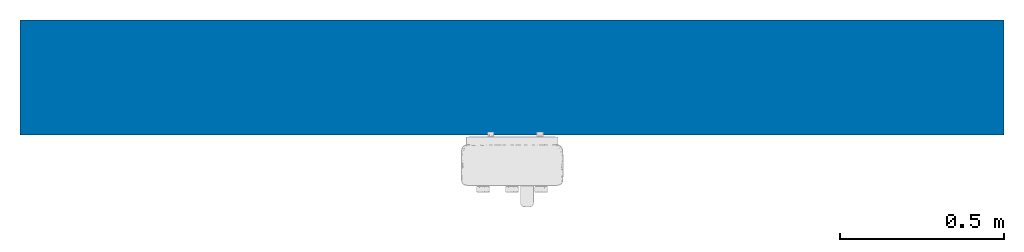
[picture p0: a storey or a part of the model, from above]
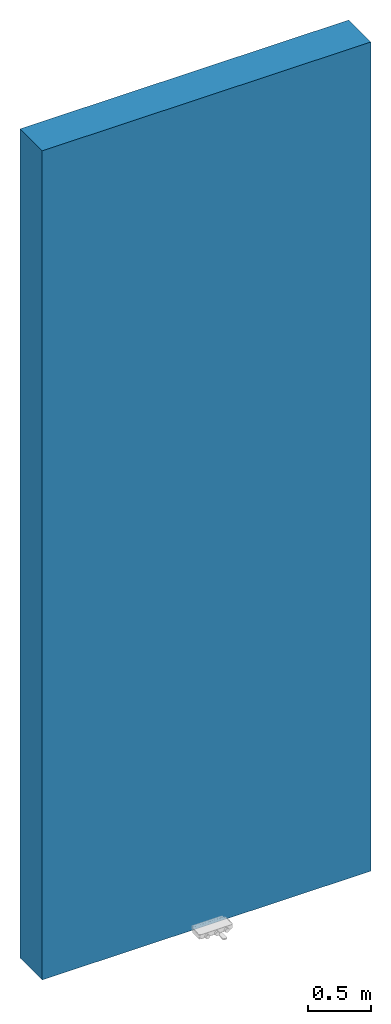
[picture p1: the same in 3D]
Properties of the parts of a building model (IFC2X3)

# File
Description: ViewDefinition [CoordinationView_V2.0]
File name: 0001
Time: 2024-09-07T14:57:09
Written by: The EXPRESS Data Manager Version 5.02.0100.07 : 28 Aug 2013
Made in: 21.1.90.15 - Exporter 21.1.90.15 - Alternate UI 21.1.90.15
Comment: STEP Physical File produced by: The EXPRESS Data Manager Version 5.02.0100.07 : 28 Aug 2013 * Module: EDMstepFileFactory/EDMstandAlone * Creation date: Sat Sep 07 14:57:09 2024 * Host: DCreative * Database: C:\Users\chatp\AppData\Local\Temp\d0251054-0f9e-4ea9-8ffe-3da880dff453\642b8a77-a6af-4033-ac83-84924f873672\ifc * Database version: 5507 * Database creation date: Sat Sep 07 14:57:06 2024 * Schema: IFC2X3 * Model: DataRepository.ifc * Model creation date: Sat Sep 07 14:57:06 2024 * Header model: DataRepository.ifc_HeaderModel * Header model creation date: Sat Sep 07 14:57:06 2024 * EDMuser: sdai-user * EDMgroup: sdai-group * License ID and type: 5605 : Permanent license. Expiry date: * EDMstepFileFactory options: 020000

# IfcProject, 0001
LongName: Project Name; Phase: Project Status

# IfcSite, Default
RefLatitude: 42, 21, 31, 181945; RefLongitude: -71, -3, -24, -263305; RefElevation: 0 mm
Pset_ProductRequirements - Category: Project Information

# IfcBuilding
Pset_BuildingCommon - NumberOfStoreys: 1
Pset_ProductRequirements - Category: Project Information

# IfcBuildingStorey: Level:8mm Head, Level 1
LongName: Level 1; Elevation: 0 mm
Pset_AirSideSystemInformation - Name: Level 1
Pset_ProductRequirements - Name: Level 1; Category: Levels

# IfcDistributionPort (2)
Description: Flow; FlowDirection: SOURCEANDSINK

# IfcFlowTerminal: FFAS4954-609500BC0_REVIT:CPF300H1H2#BN2, FFAS4954-609500BC0_REVIT:CPF300H1H2#BN2:349378
In: Level 1
Type - Material: Brass, COTTO - Brass - Black
Type - Pset_ManufacturerOccurrence - BarCode: 8852410301381
Type - Pset_ManufacturerTypeInformation - Manufacturer: COTTO
Type - Pset_ProductRequirements - Category: Plumbing Fixtures
Type - Pset_QuantityTakeOff - Reference: CPF300H1H2#BN2
Material: COTTO - Brass - Black
Pset_DistributionFlowElementCommon - Reference: CPF300H1H2#BN2; sets with these values: 2

# IfcWallStandardCase: Basic Wall:Exterior - Brick on Mtl. Stud, Basic Wall:Exterior - Brick on Mtl. Stud:347044
In: Level 1
Type - PredefinedType: STANDARD
Type - Pset_ElementShading - Roughness: 914.4 mm
Type - Pset_ProductRequirements - Category: Walls
Type - Pset_QuantityTakeOff - Reference: Exterior - Brick on Mtl. Stud
Type - Pset_ReinforcementBarPitchOfWall - Reference: Exterior - Brick on Mtl. Stud
Type - Pset_WallCommon - Reference: Exterior - Brick on Mtl. Stud; IsExternal: no
Pset_QuantityTakeOff - sets with these values: 2
Pset_WallCommon - IsExternal: yes; ExtendToStructure: no; LoadBearing: no
